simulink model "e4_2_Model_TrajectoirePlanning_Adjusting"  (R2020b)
settings: Solver=FixedStepAuto  StartTime=0.0  StopTime=100  FixedStep=sampleTime  RelTol=1e-3  EnableMultiTasking=on
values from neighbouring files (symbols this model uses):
  k2_d_x = 1/2    (= 0.5)    [e4_2_Model_TrajectoirePlanning_code.m]    (also in e4_1_Model_TrajectoirePlanning_HITL_code.m; e4_3_Model_TrajectoirePlanning_code.m; e4_1_TF_TrajectoirePlanning_code.m = 1; e4_1_Model_TrajectoirePlanning_code.m)
  k2_d_y = 1/2.65    (= 0.377358490566)    [e4_2_Model_TrajectoirePlanning_code.m]    (also in e4_1_Model_TrajectoirePlanning_HITL_code.m; e4_3_Model_TrajectoirePlanning_code.m; e4_1_TF_TrajectoirePlanning_code.m = 1; e4_1_Model_TrajectoirePlanning_code.m)
  k2_d_z = 10    [e4_2_Model_TrajectoirePlanning_code.m]    (also in e4_1_Model_TrajectoirePlanning_HITL_code.m; e4_3_Model_TrajectoirePlanning_code.m; e4_1_TF_TrajectoirePlanning_code.m; e4_1_Model_TrajectoirePlanning_code.m)
  k2_p_x = 1/1.55    (= 0.645161290323)    [e4_2_Model_TrajectoirePlanning_code.m]    (also in e4_1_Model_TrajectoirePlanning_HITL_code.m; e4_3_Model_TrajectoirePlanning_code.m; e4_1_TF_TrajectoirePlanning_code.m = 1.25; e4_1_Model_TrajectoirePlanning_code.m)
  k2_p_y = 1/2.5    (= 0.4)    [e4_2_Model_TrajectoirePlanning_code.m]    (also in e4_1_Model_TrajectoirePlanning_HITL_code.m; e4_3_Model_TrajectoirePlanning_code.m; e4_1_TF_TrajectoirePlanning_code.m = 1.25; e4_1_Model_TrajectoirePlanning_code.m)
  k2_p_yaw = 1.6    [e4_2_Model_TrajectoirePlanning_code.m]    (also in e4_1_Model_TrajectoirePlanning_HITL_code.m; e4_3_Model_TrajectoirePlanning_code.m; e4_1_TF_TrajectoirePlanning_code.m; e4_1_Model_TrajectoirePlanning_code.m)
  k2_p_z = 1    [e4_2_Model_TrajectoirePlanning_code.m]    (also in e4_1_Model_TrajectoirePlanning_HITL_code.m; e4_3_Model_TrajectoirePlanning_code.m; e4_1_TF_TrajectoirePlanning_code.m; e4_1_Model_TrajectoirePlanning_code.m)
  Kd_RP_AgngleRate = 0.005    [startSimulation.m]    (also in start.m)
  Kd_YAW_AngleRate = 0.05    [startSimulation.m]    (also in start.m)
  Ki_RP_AgngleRate = 0.01    [startSimulation.m]    (also in start.m)
  Ki_YAW_AngleRate = 0.8    [startSimulation.m]    (also in start.m)
  Kp_RP_AgngleRate = 0.55    [startSimulation.m]    (also in start.m)
  Kp_RP_ANGLE = 6.5    [startSimulation.m]    (also in start.m)
  Kp_YAW_AngleRate = 3.2    [startSimulation.m]    (also in start.m)
  sampleTime = 0.01    [startSimulation.m]    (also in start.m)
  saturation_psi = 2    [startSimulation.m]    (also in start.m)
  saturation_x = 2    [startSimulation.m]    (also in start.m)
  saturation_y = 2    [startSimulation.m]    (also in start.m)
  saturation_z = 2    [startSimulation.m]    (also in start.m)
undefined symbols (not defined in the file or in its folder): Earth, earthRadius, KiPitchAttitude, KiRollAttitude, ModelInit, ModelParam, Receive, Send, WGS84
libraries: simulink x16, sharedtransform x3, aerolibtransform2 x3, aerolibfltsims x3, aerolibutil x2, aerolibanimutils x1, shared6dof x1, aerolibatmos2 x1, aerolibconvert2 x1, aerolibobsolete x1, aerolibasang x1, aerolibnav x1
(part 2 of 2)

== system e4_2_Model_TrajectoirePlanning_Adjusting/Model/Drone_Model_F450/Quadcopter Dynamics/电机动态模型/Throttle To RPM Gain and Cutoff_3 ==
  note: Output equals linearly scaled RPM for given throttle input if throttle input >=Throttle Cuttoff (minThr) else output is zero.
  In5 : Inport
  Constant : Constant  Value=ModelParam.motorWb
  Gain : Gain  Gain=ModelParam.motorCr
  Minimum Throttle Cutoff : simulink/Logic and Bit Operations/Compare To Constant  relop=>=  const=ModelParam.motorMinThr  OutDataTypeStr=uint8
  Product : Product
  Sum1 : Sum  Inputs=++|
  Out5 : Outport  VectorParamsAs1DForOutWhenUnconnected=off
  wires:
  Minimum Throttle Cutoff/1 -> Product/2
  Product/1 -> Out5/1
  In5/1 -> Minimum Throttle Cutoff/1, Gain/1
  Gain/1 -> Sum1/2
  Sum1/1 -> Product/1
  Constant/1 -> Sum1/1

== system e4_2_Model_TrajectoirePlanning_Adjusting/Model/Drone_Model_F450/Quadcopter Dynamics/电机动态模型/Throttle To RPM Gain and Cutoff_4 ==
  note: Output equals linearly scaled RPM for given throttle input if throttle input >=Throttle Cuttoff (minThr) else output is zero.
  In5 : Inport
  Constant : Constant  Value=ModelParam.motorWb
  Gain : Gain  Gain=ModelParam.motorCr
  Minimum Throttle Cutoff : simulink/Logic and Bit Operations/Compare To Constant  relop=>=  const=ModelParam.motorMinThr  OutDataTypeStr=uint8
  Product : Product
  Sum1 : Sum  Inputs=++|
  Out5 : Outport  VectorParamsAs1DForOutWhenUnconnected=off
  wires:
  Minimum Throttle Cutoff/1 -> Product/2
  Product/1 -> Out5/1
  In5/1 -> Minimum Throttle Cutoff/1, Gain/1
  Gain/1 -> Sum1/2
  Sum1/1 -> Product/1
  Constant/1 -> Sum1/1

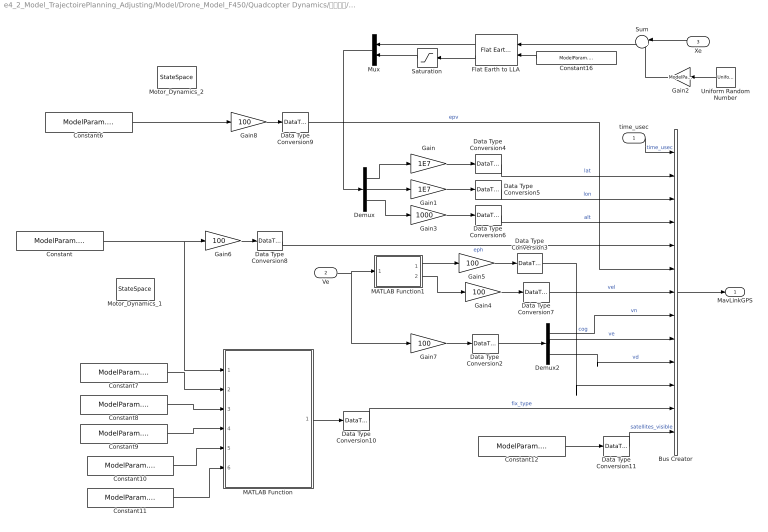
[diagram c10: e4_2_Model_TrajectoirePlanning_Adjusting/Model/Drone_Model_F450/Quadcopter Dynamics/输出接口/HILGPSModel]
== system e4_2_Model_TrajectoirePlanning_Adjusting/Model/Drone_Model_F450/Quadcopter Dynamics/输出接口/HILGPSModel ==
  time_usec : Inport
  Ve : Inport  Port=2
  Xe : Inport  Port=3
  Bus Creator : BusCreator  Inputs=13
  Constant : Constant  Value=ModelParam.GPSEphFinal
  Constant10 : Constant  Value=ModelParam.GPSFix2DFix
  Constant11 : Constant  Value=ModelParam.GPSFixNoFix
  Constant12 : Constant  Value=ModelParam.GPSSatsVisible
  Constant16 : Constant  Value=ModelParam.envAltitude
  Constant6 : Constant  Value=ModelParam.GPSEpvFinal
  Constant7 : Constant  Value=ModelParam.GPSEphMin3d
  Constant8 : Constant  Value=ModelParam.GPSEphMin2d
  Constant9 : Constant  Value=ModelParam.GPSFix3DFix
  Data Type Conversion10 : DataTypeConversion  OutDataTypeStr=uint8
  Data Type Conversion11 : DataTypeConversion  OutDataTypeStr=uint8
  Data Type Conversion2 : DataTypeConversion  OutDataTypeStr=int16
  Data Type Conversion{3,7..9} (4 alike) : DataTypeConversion  OutDataTypeStr=uint16
  Data Type Conversion4 : DataTypeConversion  OutDataTypeStr=int32
  Data Type Conversion5 : DataTypeConversion  OutDataTypeStr=int32
  Data Type Conversion6 : DataTypeConversion  OutDataTypeStr=int32
  Demux : Demux  Outputs=3
  Demux2 : Demux  Outputs=3
  Flat Earth to LLA : aerolibtransform2/Flat Earth to LLA  units=Metric (MKS)  ptype=Earth (WGS84)  F=1/298.257223563  R=6378137  LL0=[ModelParam.envLatitude ModelParam.envLongitude]  psi=0
  Gain : Gain  Gain=1E7
  Gain1 : Gain  Gain=1E7
  Gain2 : Gain  Gain=ModelParam.noiseUpperGPS
  Gain3 : Gain  Gain=1000
  Gain{4..8} (5 alike) : Gain  Gain=100
  MATLAB Function : MATLAB Function  TreatAsAtomicUnit=on
  MATLAB Function1 : MATLAB Function  TreatAsAtomicUnit=on
  Motor_Dynamics_1 : StateSpace  Commented=on  A=-1/ModelParam.GPSEphTimeConstant  C=1/ModelParam.GPSEphTimeConstant  D=0  InitialCondition=ModelParam.GPSEphInitial*ModelParam.GPSEphTimeConstant
  Motor_Dynamics_2 : StateSpace  Commented=on  A=-1/ModelParam.GPSEpvTimeConstant  C=1/ModelParam.GPSEpvTimeConstant  D=0  InitialCondition=ModelParam.GPSEpvInitial*ModelParam.GPSEpvTimeConstant
  Mux : Mux  Inputs=2
  Saturation : Saturate  UpperLimit=100000  LowerLimit=0
  Sum : Sum  Inputs=|++
  Uniform Random Number : UniformRandomNumber  Minimum=[-1,-1,-3]  Maximum=[1,1,3]  Seed=[14524,7875,698]  SampleTime=ModelParam.timeSamp
  MavLinkGPS : Outport  VectorParamsAs1DForOutWhenUnconnected=off
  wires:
  Data Type Conversion8/1 -> Bus Creator/5  "eph"
  Gain8/1 -> Data Type Conversion9/1
  Gain6/1 -> Data Type Conversion8/1
  Constant/1 -> MATLAB Function/1(eph), Gain6/1
  Data Type Conversion9/1 -> Bus Creator/6  "epv"
  time_usec/1 -> Bus Creator/1  "time_usec"
  Ve/1 -> Gain7/1, MATLAB Function1/1(u)
  Gain/1 -> Data Type Conversion4/1
  Gain1/1 -> Data Type Conversion5/1
  Gain3/1 -> Data Type Conversion6/1
  Data Type Conversion4/1 -> Bus Creator/2  "lat"
  Data Type Conversion5/1 -> Bus Creator/3  "lon"
  Data Type Conversion6/1 -> Bus Creator/4  "alt"
  Demux2/1 -> Bus Creator/8  "vn"
  Demux2/2 -> Bus Creator/9  "ve"
  Demux2/3 -> Bus Creator/10  "vd"
  Gain7/1 -> Data Type Conversion2/1
  Data Type Conversion2/1 -> Demux2/1
  Gain4/1 -> Data Type Conversion7/1
  MATLAB Function1/2(v) -> Gain4/1
  Data Type Conversion7/1 -> Bus Creator/7  "vel"
  Gain5/1 -> Data Type Conversion3/1
  MATLAB Function1/1(cot) -> Gain5/1
  Data Type Conversion3/1 -> Bus Creator/11  "cog"
  Constant9/1 -> MATLAB Function/4(Fix3D)
  Data Type Conversion11/1 -> Bus Creator/13  "satellites_visible"
  Constant7/1 -> MATLAB Function/2(eph3d)
  Data Type Conversion10/1 -> Bus Creator/12  "fix_type"
  MATLAB Function/1(FixType) -> Data Type Conversion10/1
  Constant8/1 -> MATLAB Function/3(eph2d)
  Bus Creator/1 -> MavLinkGPS/1
  Constant10/1 -> MATLAB Function/5(Fix2D)
  Constant11/1 -> MATLAB Function/6(FixNo)
  Constant12/1 -> Data Type Conversion11/1
  Flat Earth to LLA/2 -> Saturation/1
  Saturation/1 -> Mux/2
  Constant16/1 -> Flat Earth to LLA/2
  Mux/1 -> Demux/1
  Xe/1 -> Sum/1
  Flat Earth to LLA/1 -> Mux/1
  Demux/1 -> Gain/1
  Demux/2 -> Gain1/1
  Demux/3 -> Gain3/1
  Uniform Random Number/1 -> Gain2/1
  Sum/1 -> Flat Earth to LLA/1
  Gain2/1 -> Sum/2
  Constant6/1 -> Gain8/1

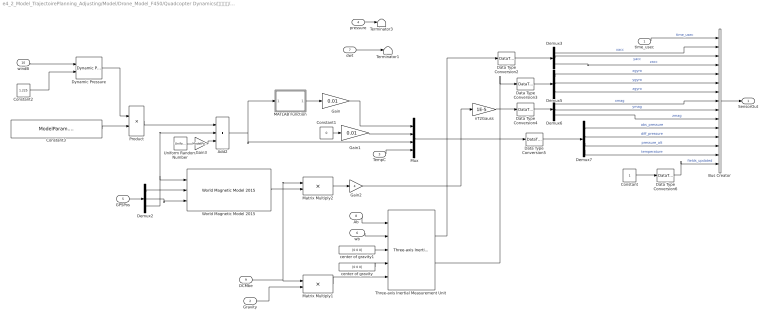
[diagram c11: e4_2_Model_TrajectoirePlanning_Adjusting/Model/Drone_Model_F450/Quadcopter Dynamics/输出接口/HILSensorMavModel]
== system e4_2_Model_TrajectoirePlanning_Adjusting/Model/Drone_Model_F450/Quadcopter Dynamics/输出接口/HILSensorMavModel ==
  time_usec : Inport
  Gravity : Inport  Port=2
  TempC : Inport  Port=3
  pressure : Inport  Port=4
  GPSPos : Inport  Port=5
  wb : Inport  Port=6
  dwt : Inport  Port=7
  Ab : Inport  Port=8
  DCMbe : Inport  Port=9
  windB : Inport  Port=10
  Add2 : Sum  Inputs=+++
  Bus Creator : BusCreator  Inputs=15
  Constant : Constant
  Constant1 : Constant  Value=0
  Constant2 : Constant  Value=1.225
  Constant3 : Constant  Value=ModelParam.noiseBaroCoupleWithSpeed
  Data Type Conversion{2..5} (4 alike) : DataTypeConversion  OutDataTypeStr=single
  Data Type Conversion6 : DataTypeConversion  OutDataTypeStr=uint32
  Demux{2..3,5..6} (4 alike) : Demux  Outputs=3
  Demux7 : Demux
  Dynamic Pressure : aerolibasang/Dynamic Pressure
  Gain : Gain  Gain=0.01
  Gain1 : Gain  Gain=0.01
  Gain2 : Gain  Gain=4
  Gain3 : Gain  Gain=ModelParam.noiseUpperBaro
  MATLAB Function : MATLAB Function  TreatAsAtomicUnit=on
  Matrix Multiply1 : Product  Multiplication=Matrix(*)
  Matrix Multiply2 : Product  Multiplication=Matrix(*)
  Mux : Mux
  Product : Product
  Terminator1 : Terminator
  Terminator3 : Terminator
  Three-axis Inertial Measurement Unit : aerolibnav/Three-axis Inertial Measurement Unit  units=Metric (MKS)  imu=[0 0 0]  i_Ts=0  dtype_a=off  w_a=190  z_a=0.707  a_sf_cc=[0.98 0 0; 0 0.98 0; 0 0 0.98]  a_bias=[0 0 0]  a_sat="[-19.62  -19.62  -19.62 19.62 19.62 19.62]"  dtype_g=off  w_g=190  z_g=0.707  g_sf_cc=[0.98 0 0; 0 0.98 0; 0 0 0.98]  g_bias=[0 0 0]  g_sens=[0 0 0]  g_sat="[-4.36  -4.36  -4.36 4.36 4.36 4.36]"  i_rand=off  i_seeds=[23093 23094 23095 23096 23097 23098]  i_pow=ModelParam.noisePowerIMU*[0.0000005 0.0000005 0.0000005 0.000000002 0.000000002 0.000000002]
  Uniform Random Number : UniformRandomNumber  Seed=15634  SampleTime=ModelParam.timeSamp
  World Magnetic Model 2015 : aerolibgravity2/World Magnetic Model 2015  units=Metric (MKS)  time_in=off  month=May  day=1  year=2017  action=Error  h_out=off  dec_out=off  inc_out=off  ti_out=off
  center of gravity : Constant  Value=[0 0 0]
  center of gravity1 : Constant  Value=[0 0 0]
  nT2Gauss : Gain  Gain=1E-5
  SensorOut : Outport  VectorParamsAs1DForOutWhenUnconnected=off
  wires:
  center of gravity/1 -> Three-axis Inertial Measurement Unit/4
  Demux3/3 -> Bus Creator/4  "zacc"
  Data Type Conversion3/1 -> Demux5/1
  Demux5/1 -> Bus Creator/5  "xgyro"
  nT2Gauss/1 -> Data Type Conversion4/1
  Data Type Conversion2/1 -> Demux3/1
  Demux3/2 -> Bus Creator/3  "yacc"
  Demux3/1 -> Bus Creator/2  "xacc"
  World Magnetic Model 2015/1 -> Matrix Multiply2/2
  Demux7/4 -> Bus Creator/14  "temperature"
  Demux5/3 -> Bus Creator/7  "zgyro"
  Data Type Conversion4/1 -> Demux6/1
  Demux6/1 -> Bus Creator/8  "xmag"
  Demux5/2 -> Bus Creator/6  "ygyro"
  Demux7/1 -> Bus Creator/11  "abs_pressure"
  Mux/1 -> Data Type Conversion5/1
  TempC/1 -> Mux/4
  Bus Creator/1 -> SensorOut/1
  Demux6/3 -> Bus Creator/10  "zmag"
  Data Type Conversion5/1 -> Demux7/1
  Demux6/2 -> Bus Creator/9  "ymag"
  Demux7/3 -> Bus Creator/13  "pressure_alt"
  Demux7/2 -> Bus Creator/12  "diff_pressure"
  GPSPos/1 -> Demux2/1
  Ab/1 -> Three-axis Inertial Measurement Unit/1
  time_usec/1 -> Bus Creator/1  "time_usec"
  Constant/1 -> Data Type Conversion6/1
  Data Type Conversion6/1 -> Bus Creator/15  "fields_updated"
  Gain/1 -> Mux/1
  Gain1/1 -> Mux/2
  Gravity/1 -> Matrix Multiply1/2
  DCMbe/1 -> Matrix Multiply1/1, Matrix Multiply2/1
  Matrix Multiply1/1 -> Three-axis Inertial Measurement Unit/5
  Three-axis Inertial Measurement Unit/1 -> Data Type Conversion2/1
  Three-axis Inertial Measurement Unit/2 -> Data Type Conversion3/1
  Demux2/1 -> World Magnetic Model 2015/2
  Demux2/2 -> World Magnetic Model 2015/3
  Demux2/3 -> Add2/2, World Magnetic Model 2015/1
  Add2/1 -> Mux/3, MATLAB Function/1(h)
  MATLAB Function/1(p) -> Gain/1
  pressure/1 -> Terminator3/1
  Constant1/1 -> Gain1/1
  Matrix Multiply2/1 -> Gain2/1
  Gain2/1 -> nT2Gauss/1
  wb/1 -> Three-axis Inertial Measurement Unit/2
  center of gravity1/1 -> Three-axis Inertial Measurement Unit/3
  dwt/1 -> Terminator1/1
  Uniform Random Number/1 -> Gain3/1
  windB/1 -> Dynamic Pressure/1
  Constant2/1 -> Dynamic Pressure/2
  Constant3/1 -> Product/2
  Dynamic Pressure/1 -> Product/1
  Product/1 -> Add2/1
  Gain3/1 -> Add2/3

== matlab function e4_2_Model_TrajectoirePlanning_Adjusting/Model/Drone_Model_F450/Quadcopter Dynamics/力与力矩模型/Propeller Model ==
function [Fb,Fd,Mb] = fcn(uavType,w,R,Cm,Ct,Jm,wb,Vb,Cd)
% This is control effectiveness model, where Fb is the force produced by motors, Mb is
% the moment produced by motors, and Fd is the resistance produced by the air.
% The gyroscopic torque is not considered here.

 %P=wb(1);Q=wb(2);

 switch uavType
     case 0
 %%叉字型
 M_rctcm = [-sin(pi/4)*R*Ct,sin(pi/4)*R*Ct,sin(pi/4)*R*Ct,-sin(pi/4)*R*Ct;sin(pi/4)*R*Ct,-sin(pi/4)*R*Ct,sin(pi/4)*R*Ct,-sin(pi/4)*R*Ct;Cm,Cm,-Cm,-Cm];
 %tau_motorGyro = [-Q*Jm*(w(1)+w(2)-w(3)-w(4)); P*Jm*(w(1)+w(2)-w(3)-w(4)); 0]; 
 Mb = M_rctcm*(w.^2);%+tau_motorGyro; 
     case 1
%%+字型
 M_rctcm = [-R*Ct,R*Ct,0,0;0,0,R*Ct,-R*Ct;Cm,Cm,-Cm,-Cm];
 %tau_motorGyro = [-Q*Jm*(w(1)+w(2)-w(3)-w(4)); P*Jm*(w(1)+w(2)-w(3)-w(4)); 0];
 Mb = M_rctcm*(w.^2);%+tau_motorGyro; 
     otherwise
      Mb = [0;0;0];    
 end
 
 Fb = [0; 0; -sum(Ct*(w.^2))]; 
 Fd = -Cd*Vb.*abs(Vb)*0.5;
end

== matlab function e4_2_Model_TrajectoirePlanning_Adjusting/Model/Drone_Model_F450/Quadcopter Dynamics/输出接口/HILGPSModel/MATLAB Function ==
function FixType = fcn(eph,eph3d,eph2d,Fix3D,Fix2D,FixNo)
if eph <= eph3d
    FixType=Fix3D;
elseif eph <= eph2d
    FixType=Fix2D;
else
    FixType=FixNo;
end

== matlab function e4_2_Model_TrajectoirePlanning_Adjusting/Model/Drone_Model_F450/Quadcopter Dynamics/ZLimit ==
function Xee = fcn(zt,xe)
Xee=xe;
if Xee(3)>zt
    Xee(3)=zt;
end

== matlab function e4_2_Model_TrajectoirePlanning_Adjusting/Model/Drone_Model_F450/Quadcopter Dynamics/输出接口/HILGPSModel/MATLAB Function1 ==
function [cot,v] = Ang360(u)
 cot=atan2d(u(2),u(1));
if cot<0
    cot=cot+360;
end

v=norm(u);

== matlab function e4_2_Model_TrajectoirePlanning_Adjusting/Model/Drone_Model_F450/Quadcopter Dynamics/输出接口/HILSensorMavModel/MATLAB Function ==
function p = fcn(h)
p=((1-h/0.3048/145366.45))^(1/0.190284)*101325;

== matlab function e4_2_Model_TrajectoirePlanning_Adjusting/Control Input/Bloc Test 
Segment/Route Approaching Y ==
function P_d = fcn(P_feedback, P_init, P_final)

% determine the constants
a0  = 2;

% the parameters of PD controller: 1/k2
% according to P287 of 《多旋翼飞行器设计与控制》,
% these two parameters should be equal? Is that true?

% global k2_p_y;
% global k2_d_y;
% k2_p_y=0.1;
% k2_d_y=0.1;

% the parameter of 'approaching'
k0_y=0.1;
k1_y=1;

persistent P_static;
if isempty(P_static)
    P_static=0; % the initilized value of position for giving a initial UAV position
else
    P_static = P_feedback;
end

% P_static = P_feedback;

% the iterative process
P_perp = P_final+(P_init-P_final)*((P_static-P_final)'*(P_init-P_final))/(norm(P_final-P_init + 0.000001))^2;
% this extra '+ 0.000001' is for avoiding that 
% the zero denominator turns to zero.

temp  = k1_y*satgd(((k0_y/k1_y)*(P_final - P_static)+(P_perp-P_static)),a0);
% temp  = k0_y*satgd(((P_final - P_static)+(k1_y/k0_y)*(P_perp-P_static)),a0);

P_d = P_static + temp;

== matlab function e4_2_Model_TrajectoirePlanning_Adjusting/Control Input/Bloc Test 
Segment/Route Approaching X ==
function P_d = fcn(P_feedback, P_init, P_final)

% determine the constants
a0  = 2;

% the parameters of PD controller: 1/k2
% according to P287 of 《多旋翼飞行器设计与控制》,
% these two parameters should be equal? Is that true?

% global k2_p_x;
% global k2_d_x;
% k2_p_x=0.1;
% k2_d_x=0.1;

% the parameter of 'approaching'
k0_x=0.1;
k1_x=1;

persistent P_static;
if isempty(P_static)
    P_static=0; % the initilized value of position for giving a initial UAV position
else
    P_static = P_feedback;
end



% the iterative process
P_perp = P_final+(P_init-P_final)*((P_static-P_final)'*(P_init-P_final))/(norm(P_final-P_init + 0.000001))^2;
% this extra '+ 0.000001' is for avoiding that 
% the zero denominator turns to zero.

temp  = k1_x*satgd(((k0_x/k1_x)*(P_final - P_static)+(P_perp-P_static)),a0);
% temp  = k0_x*satgd(((P_final - P_static)+(k1_x/k0_x)*(P_perp-P_static)),a0);

P_d = P_static + temp;

== matlab function e4_2_Model_TrajectoirePlanning_Adjusting/Control Input/Bloc Test 
Segment/Route Approaching H ==
function P_d = fcn(P_feedback, P_init, P_final)

% determine the constants
a0  = 10;

% the parameters of PD controller: 1/k2
% according to P287 of 《多旋翼飞行器设计与控制》,
% these two parameters should be equal? Is that true?

% global k2_p_z;
% global k2_d_z;
% k2_p_z=0.1;
% k2_d_z=0.1;

% the parameter of 'approaching'
k0_z=0.1;
k1_z=1;

persistent P_static;
if isempty(P_static)
    P_static=0; % the initilized value of position for giving a initial UAV position
end

P_static = P_feedback;

% the iterative process
P_perp = P_final+(P_init-P_final)*((P_static-P_final)'*(P_init-P_final))/(norm(P_final-P_init + 0.000001))^2;
% this extra '+ 0.000001' is for avoiding that 
% the zero denominator turns to zero.
temp  = satgd(k0_z*(P_final - P_static)+k1_z*(P_perp-P_static),a0);
P_d = P_static + temp;

== matlab function e4_2_Model_TrajectoirePlanning_Adjusting/Control Input/Bloc Test 
Segment/Route Approaching Psi ==
function P_d = fcn(P_feedback, P_init, P_final)

% determine the constants
a0  = 10;

% the parameters of PD controller: 1/k2
% according to P287 of 《多旋翼飞行器设计与控制》,
% these two parameters should be equal? Is that true?

% global k2_p_yaw;
% global k2_d_yaw;
% k2_p_yaw=0.1;
% k2_d_yaw=0.1;

% the parameter of 'approaching'
k0_yaw=0.1;
k1_yaw=1;

persistent P_static;
if isempty(P_static)
    P_static=0; % the initilized value of position for giving a initial UAV position
end

P_static = P_feedback;

% the iterative process
P_perp = P_final+(P_init-P_final)*((P_static-P_final)'*(P_init-P_final))/(norm(P_final-P_init + 0.000001))^2;
% this extra '+ 0.000001' is for avoiding that 
% the zero denominator turns to zero.
temp  = satgd(k0_yaw*(P_final - P_static)+k1_yaw*(P_perp-P_static),a0);
P_d = P_static + temp;

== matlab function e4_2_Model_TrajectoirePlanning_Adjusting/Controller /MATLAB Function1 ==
function [theta,phi] = fcn(eax,eay)
g=9.8;

theta =-eax/g;% vx
phi =eay/g;% vy

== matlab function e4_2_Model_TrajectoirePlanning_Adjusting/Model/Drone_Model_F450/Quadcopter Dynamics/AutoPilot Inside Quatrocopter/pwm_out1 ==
function [M1, M2, M3, M4] = motor_mixer(Roll, Pitch, Yaw, Thrust)

idle_PWM = 1000;

% Quad XROLL （根据QP里面的叉字形结构的文字）
% M1 = ((Pitch+ Yaw)+Thrust-Roll) * 1000 + idle_PWM;
 %M2 = ((Pitch - Yaw)+Thrust+Roll) * 1000 + idle_PWM;
 %M3 = ((Roll +Yaw) + Thrust-Pitch) * 1000 + idle_PWM;
 %M4 = ((-Roll - Pitch-Yaw) + Thrust) * 1000 + idle_PWM;
% M5 = 1000;
% M6 = 1000;
% M7 = 1000;
% M8 = 1000;
%qp上实际的输出
M1 = (Thrust+Pitch-Roll+Yaw)*1000  + idle_PWM;
M2 = (Thrust-Pitch +Roll+Yaw)*1000 + idle_PWM;
M3 = (Thrust+Roll+Pitch-Yaw)*1000  + idle_PWM;
M4 = (Thrust-Roll- Pitch -Yaw)*1000 + idle_PWM;
% Quad +
 %M1 = ((Pitch - Yaw) * Thrust / 2 + Thrust) * 1000 + idle_PWM;
 %M2 = ((-Roll + Yaw) * Thrust / 2 + Thrust) * 1000 + idle_PWM;
% M3 = ((-Pitch - Yaw) * Thrust / 2 + Thrust) * 1000 + idle_PWM;
 %M4 = ((Roll + Yaw) * Thrust / 2 + Thrust) * 1000 + idle_PWM;
% M5 = 1000;
% M6 = 1000;
% M7 = 1000;
% M8 = 1000;

% Hex X
% M1 = ((Pitch + Roll / 2 - Yaw) * Thrust / 2 + Thrust) * 1000 + idle_PWM;
% M2 = ((Pitch - Roll / 2 + Yaw) * Thrust / 2 + Thrust) * 1000 + idle_PWM;
% M3 = ((-Roll - Yaw) * Thrust / 2 + Thrust) * 1000 + idle_PWM;
% M4 = ((-Pitch - Roll / 2 + Yaw) * Thrust / 2 + Thrust) * 1000 + idle_PWM;
% M5 = ((-Pitch + Roll / 2 - Yaw) * Thrust / 2 + Thrust) * 1000 + idle_PWM;
% M6 = ((Roll + Yaw) * Thrust / 2 + Thrust) * 1000 + idle_PWM;
% M7 = 1000;
% M8 = 1000;

% Hex X (From Adam)
%M1 = uint16(single(((-Roll - Yaw) * Thrust / 3 + Thrust) * single(1000))) + idle_PWM;
%M2 = uint16(single(((Roll + Yaw) * Thrust / 3 + Thrust) * single(1000))) + idle_PWM;
%M3 = uint16(single(((Pitch + (Roll / 2) - Yaw) * Thrust / 3 + Thrust) * single(1000))) + idle_PWM;
%M4 = uint16(single(((-Pitch - (Roll / 2) + Yaw) * Thrust / 3 + Thrust) * single(1000))) + idle_PWM;
%M5 = uint16(single(((Pitch - (Roll / 2) + Yaw) * Thrust / 3 + Thrust) * single(1000))) + idle_PWM;
%M6 = uint16(single(((-Pitch + (Roll / 2) - Yaw) * Thrust / 3 + Thrust) * single(1000))) + idle_PWM;

% Hex X (Version 2)
% Roll/Yaw
% M1 = ((-Roll - Yaw) * Thrust / 2 + Thrust) * 1000 + idle_PWM;
% M2 = ((Roll + Yaw) * Thrust / 2 + Thrust) * 1000 + idle_PWM;
% % + Pitch/Roll
% M6 = ((Pitch + Roll / 2 - Yaw) * Thrust / 2 + Thrust) * 1000 + idle_PWM;
% M4 = ((Pitch - Roll / 2 + Yaw) * Thrust / 2 + Thrust) * 1000 + idle_PWM;
% % - Pitch/Roll
% M5 = ((-Pitch - Roll / 2 + Yaw) * Thrust / 2 + Thrust) * 1000 + idle_PWM;
% M3 = ((-Pitch + Roll / 2 - Yaw) * Thrust / 2 + Thrust) * 1000 + idle_PWM;

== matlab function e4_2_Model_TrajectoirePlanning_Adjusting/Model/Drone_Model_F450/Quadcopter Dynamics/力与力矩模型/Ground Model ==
function [F1,M1,landed,takeoff] = fcn(mg,wb,Xe,Ve,Quet,terrainZ)
% This is a ground model that can provides reaction force and reaction torque

persistent z0;
if isempty(z0)
     z0=0;
end

persistent takeoffFlag;
if isempty(takeoffFlag)
     takeoffFlag=int8(0);
end

persistent landFlag;
if isempty(landFlag)
     landFlag=int8(1);
end


z=Xe(3)-z0;

 if (z<-0.3)&&(Ve(3)<-0.1)&&(takeoffFlag<0.5)
    takeoffFlag=int8(1);
    landFlag=int8(0);
 end
 
 if (z>-0.05)&&(Ve(3)>0.1)&&(landFlag<0.5)
    landFlag=int8(1);
    takeoffFlag=int8(0);
    z0=terrainZ;
 end

takeoff = takeoffFlag;
landed = landFlag;


F1=[0;0;0];
M1=[0;0;0];


if z>=0
    if Ve(3)>=1
        F1(3)=-mg(3)-1000*Ve(3);
    else
        F1(3)=-mg(3)-500*z-100*Ve(3);  
    end
    
    F1(1)=-10*Ve(1);
    F1(2)=-10*Ve(2);
    M1=-200*[Quet(2);Quet(3);Quet(4)]-10*wb;
end

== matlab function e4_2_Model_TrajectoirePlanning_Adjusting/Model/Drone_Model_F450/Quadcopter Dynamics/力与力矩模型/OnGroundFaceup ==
function y = fcn(EulerAng)

targetRoll = 0;
% if cos(EulerAng(1))<0
%     targetRoll=pi;  
% end

targetPitch = 0;
% if cos(EulerAng(2))<0
%         targetPitch=pi;
% end
    
y = [targetRoll;targetPitch;EulerAng(3)];
